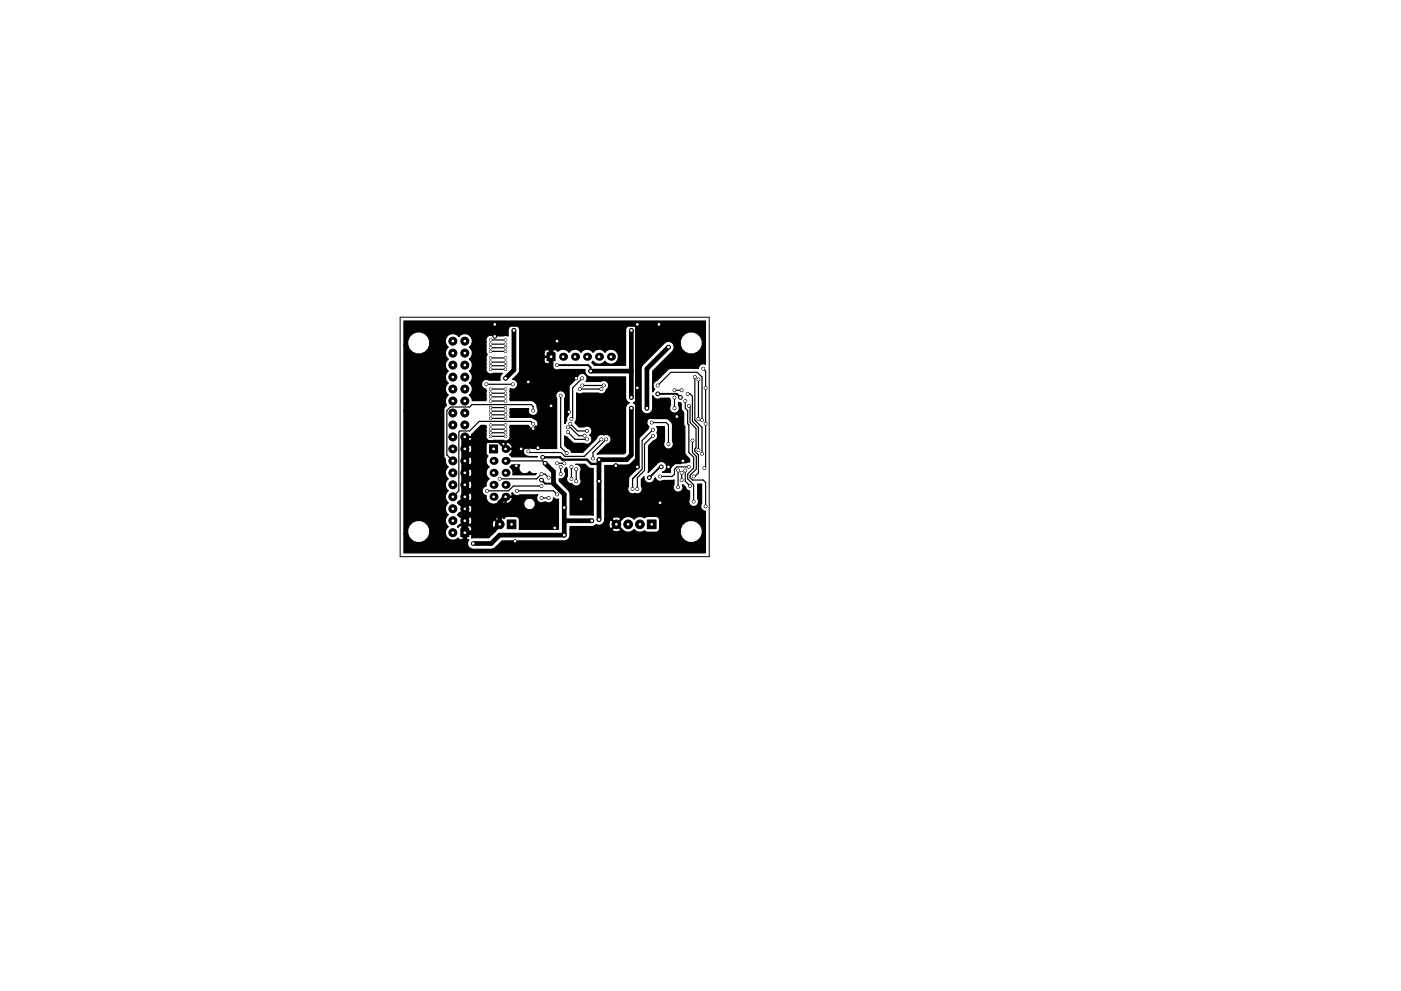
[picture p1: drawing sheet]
<svg xmlns="http://www.w3.org/2000/svg" width="297mm" height="210mm" viewBox="0 0 297 210" stroke-linecap="round" stroke-linejoin="round" font-family="sans-serif">
<path d="M84.8 67.3h65.6v50.8h-65.6z" fill="none" stroke="#000" stroke-width=".21"/>
<g fill="#000" stroke="#000" stroke-width=".21">
<path d="M116 74.8h1.7v1.7h-1.7zM103.8 94.4h1.7v1.7h-1.7zM97.7 112.2h1.7v1.7h-1.7zM107.5 110.3h1.9v1.9h-1.9zM137.3 110.3h1.8v1.9h-1.8z"/>
<circle cx="96" cy="74.9" r=".85"/>
<circle cx="96" cy="72.4" r=".85"/>
<circle cx="96" cy="77.5" r=".85"/>
<circle cx="98.6" cy="72.4" r=".85"/>
<circle cx="98.6" cy="74.9" r=".85"/>
<circle cx="98.6" cy="77.5" r=".85"/>
<circle cx="104" cy="72.1" r=".25"/>
<circle cx="104" cy="78.4" r=".25"/>
<circle cx="104" cy="73.8" r=".25"/>
<circle cx="104" cy="73" r=".25"/>
<circle cx="104" cy="75.9" r=".25"/>
<circle cx="104" cy="74.5" r=".25"/>
<circle cx="104" cy="77.6" r=".25"/>
<circle cx="104" cy="76.8" r=".25"/>
<circle cx="104.9" cy="71.4" r=".4"/>
<circle cx="104.9" cy="68.8" r=".4"/>
<circle cx="107.2" cy="75.9" r=".25"/>
<circle cx="107.2" cy="73.8" r=".25"/>
<circle cx="107.2" cy="76.8" r=".25"/>
<circle cx="107.2" cy="77.6" r=".25"/>
<circle cx="107.2" cy="73" r=".25"/>
<circle cx="107.2" cy="72.1" r=".25"/>
<circle cx="107.2" cy="74.5" r=".25"/>
<circle cx="107.2" cy="78.4" r=".25"/>
<circle cx="109" cy="70.1" r=".4"/>
<circle cx="118.1" cy="77.5" r=".3"/>
<circle cx="118.1" cy="72.4" r=".3"/>
<circle cx="125.2" cy="78.7" r=".4"/>
<circle cx="133.9" cy="70.1" r=".4"/>
<circle cx="135.1" cy="68.8" r=".4"/>
<circle cx="139.7" cy="68.8" r=".4"/>
<circle cx="141.7" cy="73.7" r=".4"/>
<circle cx="149.1" cy="78.2" r=".3"/>
<circle cx="96" cy="80" r=".85"/>
<circle cx="96" cy="87.6" r=".85"/>
<circle cx="96" cy="92.7" r=".85"/>
<circle cx="96" cy="90.2" r=".85"/>
<circle cx="96" cy="97.8" r=".85"/>
<circle cx="96" cy="82.5" r=".85"/>
<circle cx="96" cy="95.2" r=".85"/>
<circle cx="96" cy="85.1" r=".85"/>
<circle cx="98.6" cy="85.1" r=".85"/>
<circle cx="98.6" cy="92.7" r=".85"/>
<circle cx="98.6" cy="80" r=".85"/>
<circle cx="98.6" cy="97.8" r=".85"/>
<circle cx="98.6" cy="82.5" r=".85"/>
<circle cx="98.6" cy="87.6" r=".85"/>
<circle cx="98.6" cy="90.2" r=".85"/>
<circle cx="98.6" cy="95.2" r=".85"/>
<circle cx="103.1" cy="81.5" r=".3"/>
<circle cx="104" cy="88" r=".25"/>
<circle cx="104" cy="88.8" r=".25"/>
<circle cx="104" cy="84.2" r=".25"/>
<circle cx="104" cy="82.5" r=".25"/>
<circle cx="104" cy="92.6" r=".25"/>
<circle cx="104" cy="83.4" r=".25"/>
<circle cx="104" cy="91.1" r=".25"/>
<circle cx="104" cy="85.1" r=".25"/>
<circle cx="104" cy="91.8" r=".25"/>
<circle cx="104" cy="86.5" r=".25"/>
<circle cx="104" cy="90.2" r=".25"/>
<circle cx="104" cy="87.2" r=".25"/>
<circle cx="107.2" cy="92.6" r=".25"/>
<circle cx="107.2" cy="88" r=".25"/>
<circle cx="107.2" cy="91.8" r=".25"/>
<circle cx="107.2" cy="88.8" r=".25"/>
<circle cx="107.2" cy="86.5" r=".25"/>
<circle cx="107.2" cy="83.4" r=".25"/>
<circle cx="107.2" cy="91.1" r=".25"/>
<circle cx="107.2" cy="90.2" r=".25"/>
<circle cx="107.2" cy="87.2" r=".25"/>
<circle cx="107.2" cy="85.1" r=".25"/>
<circle cx="107.2" cy="84.2" r=".25"/>
<circle cx="107.2" cy="82.5" r=".25"/>
<circle cx="107.2" cy="80.3" r=".4"/>
<circle cx="108.7" cy="81.5" r=".3"/>
<circle cx="109.5" cy="98.8" r=".3"/>
<circle cx="110.5" cy="95.2" r=".3"/>
<circle cx="112" cy="81" r=".4"/>
<circle cx="112" cy="95.8" r=".3"/>
<circle cx="113" cy="87.1" r=".3"/>
<circle cx="113" cy="89.9" r=".3"/>
<circle cx="113" cy="90.9" r=".3"/>
<circle cx="114" cy="95" r=".4"/>
<circle cx="115.1" cy="97" r=".4"/>
<circle cx="115.6" cy="98.3" r=".4"/>
<circle cx="116.8" cy="86.1" r=".3"/>
<circle cx="118.1" cy="98.3" r=".3"/>
<circle cx="118.9" cy="99.1" r=".3"/>
<circle cx="118.9" cy="83.9" r=".3"/>
<circle cx="119.6" cy="98.3" r=".3"/>
<circle cx="120.1" cy="96.1" r=".3"/>
<circle cx="120.4" cy="91.7" r=".3"/>
<circle cx="120.4" cy="90.7" r=".3"/>
<circle cx="120.7" cy="87.4" r=".3"/>
<circle cx="120.9" cy="89.9" r=".3"/>
<circle cx="121.2" cy="99.1" r=".3"/>
<circle cx="121.2" cy="88.9" r=".3"/>
<circle cx="122.2" cy="99.6" r=".3"/>
<circle cx="122.2" cy="80.3" r=".3"/>
<circle cx="122.9" cy="82.5" r=".3"/>
<circle cx="123.4" cy="80.3" r=".3"/>
<circle cx="123.4" cy="81.8" r=".3"/>
<circle cx="124" cy="92.5" r=".3"/>
<circle cx="124.5" cy="93.2" r=".3"/>
<circle cx="124.5" cy="91.4" r=".3"/>
<circle cx="125.7" cy="97.3" r=".3"/>
<circle cx="127" cy="97.5" r=".4"/>
<circle cx="127.5" cy="93.2" r=".3"/>
<circle cx="127.5" cy="82.5" r=".3"/>
<circle cx="128" cy="81.8" r=".3"/>
<circle cx="128.5" cy="93.2" r=".3"/>
<circle cx="130.6" cy="98.8" r=".4"/>
<circle cx="133.9" cy="84.3" r=".4"/>
<circle cx="133.9" cy="86.6" r=".4"/>
<circle cx="135.1" cy="99.1" r=".4"/>
<circle cx="135.1" cy="82.3" r=".3"/>
<circle cx="137.2" cy="86.6" r=".4"/>
<circle cx="138.2" cy="89.7" r=".3"/>
<circle cx="138.4" cy="91.2" r=".3"/>
<circle cx="138.4" cy="92.5" r=".3"/>
<circle cx="139.4" cy="83.6" r=".4"/>
<circle cx="139.4" cy="81.8" r=".3"/>
<circle cx="140.2" cy="99.1" r=".4"/>
<circle cx="141.7" cy="99.1" r=".4"/>
<circle cx="141.7" cy="94.2" r=".3"/>
<circle cx="143" cy="86.6" r=".3"/>
<circle cx="143" cy="82.8" r=".3"/>
<circle cx="143" cy="84.3" r=".3"/>
<circle cx="143.5" cy="88.4" r=".4"/>
<circle cx="143.8" cy="99.8" r=".3"/>
<circle cx="144.3" cy="84.3" r=".4"/>
<circle cx="144.5" cy="82.8" r=".3"/>
<circle cx="144.8" cy="97.8" r=".4"/>
<circle cx="145.3" cy="85.1" r=".3"/>
<circle cx="145.3" cy="99.8" r=".3"/>
<circle cx="145.8" cy="83.6" r=".3"/>
<circle cx="146.1" cy="99.1" r=".3"/>
<circle cx="146.1" cy="86.1" r=".3"/>
<circle cx="146.8" cy="93.5" r=".3"/>
<circle cx="147.3" cy="80" r=".3"/>
<circle cx="148.1" cy="95.5" r=".3"/>
<circle cx="148.1" cy="88.9" r=".3"/>
<circle cx="148.1" cy="80.5" r=".3"/>
<circle cx="148.8" cy="96.3" r=".3"/>
<circle cx="148.8" cy="89.1" r=".3"/>
<circle cx="149.4" cy="99.3" r=".3"/>
<circle cx="149.6" cy="89.9" r=".3"/>
<circle cx="149.6" cy="82.3" r=".3"/>
<circle cx="96" cy="100.3" r=".85"/>
<circle cx="96" cy="110.5" r=".85"/>
<circle cx="96" cy="107.9" r=".85"/>
<circle cx="96" cy="105.4" r=".85"/>
<circle cx="96" cy="113" r=".85"/>
<circle cx="96" cy="102.9" r=".85"/>
<circle cx="98.6" cy="107.9" r=".85"/>
<circle cx="98.6" cy="110.5" r=".85"/>
<circle cx="98.6" cy="100.3" r=".85"/>
<circle cx="98.6" cy="105.4" r=".85"/>
<circle cx="98.6" cy="102.9" r=".85"/>
<circle cx="100.3" cy="115.3" r=".3"/>
<circle cx="103.3" cy="104.1" r=".3"/>
<circle cx="105.9" cy="101.6" r=".3"/>
<circle cx="106" cy="111.2" r=".92"/>
<circle cx="109.2" cy="114.8" r=".3"/>
<circle cx="109.6" cy="104.1" r=".3"/>
<circle cx="114.8" cy="101.8" r=".4"/>
<circle cx="114.8" cy="103.1" r=".3"/>
<circle cx="114.8" cy="105.7" r=".3"/>
<circle cx="114.8" cy="100.6" r=".3"/>
<circle cx="116.3" cy="101.3" r=".3"/>
<circle cx="116.3" cy="105.7" r=".3"/>
<circle cx="117.6" cy="112" r=".3"/>
<circle cx="118.1" cy="104.9" r=".3"/>
<circle cx="118.9" cy="100.6" r=".3"/>
<circle cx="119.6" cy="113.5" r=".4"/>
<circle cx="119.6" cy="107.7" r=".4"/>
<circle cx="121.2" cy="101.6" r=".3"/>
<circle cx="122.2" cy="102.1" r=".3"/>
<circle cx="123.2" cy="105.9" r=".3"/>
<circle cx="125.5" cy="110.5" r=".4"/>
<circle cx="127" cy="110.2" r=".4"/>
<circle cx="127" cy="102.1" r=".4"/>
<circle cx="130.7" cy="111.2" r=".92"/>
<circle cx="133.2" cy="111.2" r=".92"/>
<circle cx="134.1" cy="103.8" r=".3"/>
<circle cx="135.1" cy="103.8" r=".3"/>
<circle cx="135.7" cy="111.2" r=".92"/>
<circle cx="137.7" cy="101.3" r=".4"/>
<circle cx="140" cy="101.1" r=".3"/>
<circle cx="140" cy="106.7" r=".3"/>
<circle cx="143.8" cy="103.4" r=".3"/>
<circle cx="144.5" cy="101.8" r=".3"/>
<circle cx="144.5" cy="100.3" r=".3"/>
<circle cx="146.3" cy="103.1" r=".3"/>
<circle cx="147.1" cy="101.1" r=".3"/>
<circle cx="147.1" cy="106.4" r=".3"/>
<circle cx="149.6" cy="107.4" r=".3"/>
</g>
<g fill="#000">
<circle cx="119.4" cy="75.7" r=".85"/>
<circle cx="121.9" cy="75.7" r=".85"/>
<circle cx="124.5" cy="75.7" r=".85"/>
<circle cx="127" cy="75.7" r=".85"/>
<circle cx="129.5" cy="75.7" r=".85"/>
<circle cx="104.6" cy="97.8" r=".85"/>
<circle cx="107.2" cy="95.2" r=".85"/>
<circle cx="107.2" cy="97.8" r=".85"/>
<circle cx="104.6" cy="100.3" r=".85"/>
<circle cx="104.6" cy="102.9" r=".85"/>
<circle cx="104.6" cy="105.4" r=".85"/>
<circle cx="107.2" cy="105.4" r=".85"/>
<circle cx="107.2" cy="102.9" r=".85"/>
<circle cx="107.2" cy="100.3" r=".85"/>
</g>
<path d="M98.6 92.7h3.1l1 1h3l1.5 1.5M115.1 97h3.6l.6 .5h5.2l.8 .9h1.7" fill="none" stroke="#000" stroke-width=".5"/>
<path d="M104.9 68.8v2.6M118.1 77.5h6.6l.5 .5v.7M139.4 83.6h4.1l.8 .7M140.2 99.1h-.2l-2.3 2.2M144.8 97.8l-.5 .5h-1.3l-.8 .8h-.5M114.8 101.8l.8 .8h1.7" fill="none" stroke="#000" stroke-width=".4"/>
<g fill="none" stroke="#000" stroke-width="1">
<path d="M109 70.1v8.4l-1.8 1.8M116.8 68.8v23.9l-2 2h-3.8l-.5 .5M125.2 78.7h8.7M133.9 70.1v14.2M135.1 68.8v30.3h-4.3l-.2-.3M139.7 68.8h-45l-1 1v44.5l1 1h3.3l.6-.5v-1.8h5.6l1.8-1.8v-4.6l1.2-1.2M141.7 73.7l-4.5 4.5v8.4M114 94.7v.3M115.6 98.3l1.7 1.8v2.5l2.3 2.3v8.6h-13.7l-1.8 1.8h-3.8M116.8 80.8h-4.5l-.3 .2M133.9 86.6v9.9l-1.1 1h-5.8v12.7M135.1 88.4h8.4"/>
<path d="M119.6 110.5h5.9"/>
</g>
<g fill="none" stroke="#000" stroke-width=".25">
<path d="M104 78.4h3.2M104 77.6h3.2M104 76.8h3.2M104 75.9h3.2M104 74.5h3.2M104 73.8h3.2M104 73h3.2M104 72.1h3.2M116.8 72.4h1.3M149.1 78.2l.5 .5v20.4l-.2 .2M103.1 81.5h5.6M104 82.5h3.2"/>
<path d="M104 92.6h3.2M104 91.8h3.2M104 91.1h3.2M104 90.2h3.2M104 88.8h3.2M104 88h3.2M104 87.2h3.2M104 86.5h3.2M104 85.1h3.2M104 84.2h3.2M104 83.4h3.2M107.2 97.8h7.9l.5 .5"/>
<path d="M110.7 95v.2l-.1-.1M113 89.9l-.5-.5h-10.9l-2 2h-2.1l-.2 .3v12.4l-1.3 1.3M113 87.1v-.9l-.4-.4h-12.5l-.5 .6h-4.1l-.8 .7v9.4l1.3 1.3M116.6 90.9h.2M116.8 85.3v.8M116.8 90.4h-3.3l-.5 .5M118.1 98.3h1.5M118.9 83.9v11l1.2 1.2M118.9 99.1v1.5M120.4 90.7h.5l1.8 1.8h1.3M120.4 91.7l1.5 1.5h2.6M120.9 89.9l1.5 1.5h2.1"/>
<path d="M121.2 99.1v2.5M122.2 80.3l-1.6 1.5v5.6M122.2 99.6v2.5M122.9 82.5h4.6M123.4 80.3l-2 2v6.3l-.2 .3M123.4 81.8h4.6M127.5 93.2l-3.6 3.6h-4.1l-.9-.8h-6.6l-.3-.2M128.5 93.2l-2.8 2.8v1.3M135.1 81.8v.5M138.2 89.7h3l.5 .5v4M138.4 92.5l-1.7 1.7v5.6l-1.6 1.5v2.5M138.4 91.2l-2.3 2.3v6.1l-2 2v2.2"/>
<path d="M139.4 81.8l2.8-2.8h5.6l1 1v9.1M143 84.3v2.3M143 82.8h1.5M143.8 99.8v3.6M145.3 85.1v1.5l.5 .5v2.8l.2 .3v5.8l1.1 1v2.3l-1.3 1.3v1l1.3 1.3v3.5M145.3 99.8v2.3l1 1M145.8 83.6h.5l.5 .5v5.3l1.3 1.3v4.8M146 99.1h-2.5l-.5 .5v1l-.5 .5h-2.5M146 86.1l.3 .3v3.3l1.3 1.2v4.1l-.3 .2v.6l.8 .7v3.8l-.8 .8h-.2M146.8 93.5v2.5l.8 .8v2.7l-1.3 1.3v.5l.5 .5h2.3l.5 .6v5M147.3 80v9.1l1.5 1.6v5.6M148.1 80.5v8.4"/>
<path d="M109.6 104.1h7.7l.8 .8M114.8 103.1h-6l-1 1h-4.5M114.8 105.7h1.5M116.3 101.3l-.7-.7h-.8l-1 1h-7.9M144.5 100.3v1.5"/>
</g>
<path d="M98.6 92.7v20.3" fill="none" stroke="#000" stroke-width="1.5"/>
<path d="M85.6 68.1h64v9.2a1.01 1.01 0 0 0-1.5 .9h-6.2l-2.7 2.6a1.04 1.04 0 0 0-.8 .7 1.04 1.04 0 0 0 .4 1.1l-.4 .6v-4.5l4.2-4.2 .3-.4v-.9h1.3l.4 .9a2.37 2.37 0 0 0 3.9 0 2.37 2.37 0 0 0-1.5-3.7 2.37 2.37 0 0 0-2.8 2.8h-1.3a1.23 1.23 0 0 0-2-.4l-4.9 5-.1 8.8a1.23 1.23 0 0 0 1.3 1.2 1.23 1.23 0 0 0 1.2-1.2v-2.7l.1 .3a1.14 1.14 0 0 0 1.6 .3h1.9l.2 .4-.1 1.1a1.05 1.05 0 0 0 .9 1.7 1.05 1.05 0 0 0 .9-1.7v-.6h.4l.2 1.5 .4 .6v2.4l.3 .6v5.5l.2 .6 .8 .8v.6l-.8 .2h-1.9a1.76 1.76 0 0 0-1.4 2h-1.7l.4-.2a1.15 1.15 0 0 0 .2-1.8 1.15 1.15 0 0 0-1.8 .3l-1.8 1.7 .1-.4v-5.2l1.1-1.1a1.12 1.12 0 0 0 .7-1.7 1 1 0 0 0-.1-1.3h1.7v3.1a1.05 1.05 0 0 0 .8 1.7 1.05 1.05 0 0 0 .9-1.7v-3.5a1.76 1.76 0 0 0-1.4-1.3h-2.4a1.04 1.04 0 0 0-1.5 .3 1.04 1.04 0 0 0 .3 1.4l-.2 .5-2 2.1-.1 6.1-2 2.1-.1 1.9a1.04 1.04 0 0 0 .1 1.3 1.04 1.04 0 0 0 1.3 .2 1.04 1.04 0 0 0 1.3-.2 1.04 1.04 0 0 0 .1-1.3v-1.5l.5-.6a1.14 1.14 0 0 0 1 1.4 1.14 1.14 0 0 0 1.3-1l.2-.1 .1 .3a1.04 1.04 0 0 0 1.5 .2l2.3-.1v1a1.04 1.04 0 0 0 .8 1.6 1.04 1.04 0 0 0 1-1.5l.1-.1 .5 .5a1 1 0 0 0 .9 .8v1.7a1.05 1.05 0 0 0 .9 1.7 1.05 1.05 0 0 0 .8-1.7v-3.1h.8v4.2a1.03 1.03 0 0 0 .9 1.6v8.8h-64v-4.1h.8a2.37 2.37 0 0 0 3.7 1.5 2.37 2.37 0 0 0 0-3.9 2.37 2.37 0 0 0-3.7 1.5v.9h-.8v-26.1h8.3v9.4l.1 .3 .5 .6a1.54 1.54 0 0 0 .6 1.7 1.57 1.57 0 0 0 0 2.5 1.57 1.57 0 0 0 0 2.5 1.57 1.57 0 0 0 0 2.6 1.57 1.57 0 0 0 0 2.5 1.57 1.57 0 0 0 0 2.6 1.59 1.59 0 0 0-.3 2.3 1.59 1.59 0 0 0 2.3 0l.5 .4h.7l.1-.1v-1.2h.3v1.2l.1 .1h.6a1.22 1.22 0 0 0-.2 1.3 1.22 1.22 0 0 0 1.1 .7l4.3-.1 1.8-1.6 13.7-.1a1.32 1.32 0 0 0 .8-1.5h23.3l.4 .9a2.37 2.37 0 0 0 3.9 0 2.37 2.37 0 0 0-1.5-3.7 2.37 2.37 0 0 0-2.8 2.8h-23.3v-.9h8.9v.3a1.18 1.18 0 0 0 1.8-.3l-.9-.9-.9 .9h-8.9v-.6h4.6l.4-.1 .5-.3a1.14 1.14 0 0 0 1.5-.3h1.2v.6l.2 .5 .3 .1 .9-1h.4l.9 1a1.65 1.65 0 0 0 2.6 .1 1.61 1.61 0 0 0 2.3 .3l.6 .3h1.8a.74 .74 0 0 0 .7-.7v-1.9l-.2-.5-.5-.2h-1.8l-.7 .2a1.63 1.63 0 0 0-2.2 .4 1.64 1.64 0 0 0-2.6 .1l-.9 .9h-.4l-.9-.9-.3 .1-.2 .6h-1.2l.3-.9h1.6l.9 1 .9-1a1.09 1.09 0 0 0-1.8 0h-1.6v-11.3l5.1-.1 1.7-1.7 .1-10.4a1.2 1.2 0 0 0-.8-1.1 1.2 1.2 0 0 0 .8-1.2l-.1-14.7a1.23 1.23 0 0 0-1.4-.7 1.23 1.23 0 0 0-1 1.2v7.4h-6.6l-.5-.6 .2-.3a1.51 1.51 0 0 0 2.6 0 1.57 1.57 0 0 0 2.3 .3 1.57 1.57 0 0 0 0-2.4 1.57 1.57 0 0 0-2.3 .3 1.51 1.51 0 0 0-2.6 0 1.51 1.51 0 0 0-2.5 0 1.51 1.51 0 0 0-2.6 0 1.54 1.54 0 0 0-2.3-.3l-.5-.3h-.7l-.1 .2v2.6l.1 .3a1.03 1.03 0 0 0 .4 1 1.03 1.03 0 0 0 1.1 .1h5.5l-.1 .3a1.23 1.23 0 0 0 1.2 1.3h7.4v4.3a1.2 1.2 0 0 0 .8 1.2 1.2 1.2 0 0 0-.8 1.1v9.4l-.3 .3-5.7 .1 2.1-2.2a1.04 1.04 0 0 0 .8-1.3 1.04 1.04 0 0 0-1.5-.6 1.03 1.03 0 0 0-1.5 .7l-3 3h-2.3a1.01 1.01 0 0 0-.9-.9l-.6-.6v-2l.5 .2 1.4 1.3 2.3 .1a1.04 1.04 0 0 0 1.4-.3 1.04 1.04 0 0 0-.3-1.5 1.04 1.04 0 0 0 .3-1.4 1.04 1.04 0 0 0-1.4-.3h-1.1l-.9-1 .4-1v-5.3a.99 .99 0 0 0 1.2 .1h3.4a1.1 1.1 0 0 0 1.7-.7 1.04 1.04 0 0 0 .3-1.5 1.04 1.04 0 0 0-1.5-.3h-3.2l.1-.1a1.05 1.05 0 0 0-.5-1.5 1.05 1.05 0 0 0-1.4 .8l-1.8 1.9v6a.99 .99 0 0 0-.4 1.2l-.5 .7v-5.4a1.04 1.04 0 0 0-.8-1.6 1.04 1.04 0 0 0-.9 1.6l.1 10.7h-5.2l-.3-.3a1.07 1.07 0 0 0-1.6 .7 1.07 1.07 0 0 0 1.3 1.3h1.6h-5.4l-.5-.4 .6-.9-.1-.2h-1.5l.1-1.5h.2v1.2h1.2a1.08 1.08 0 0 0-1.4-1.2l-.3-.1-.6 .4-.4-.5h-2a.74 .74 0 0 0-.7 .7v1.7l.4 .6a1.51 1.51 0 0 0 .2 2.4 1.51 1.51 0 0 0 0 2.5 1.4 1.4 0 0 0-.6 1.5 1.04 1.04 0 0 0-.9 1 1.04 1.04 0 0 0 .9 1.1 1.57 1.57 0 0 0 1 1.7 1.57 1.57 0 0 0 1.9-.7l.8 .6 .3-.1v-1.2h.2v1.2a.99 .99 0 0 0 1.2-1.2h-1.5v-.2h1.5l.1-.3-.1-.3 .1-.2a1.02 1.02 0 0 0 1.6 .5h3.8l-.1 .1a1.04 1.04 0 0 0 .2 1.3 1.04 1.04 0 0 0 1.3 .1h.3a1.03 1.03 0 0 0 1.1 .1 1.03 1.03 0 0 0 .6-1 .94 .94 0 0 0 1 .3v6.4h-8.3v-2a.74 .74 0 0 0-.7-.7h-1.9l-.5 .2-.2 .3v-.2a1.18 1.18 0 0 0-1.8 .2l1.2 1.2-1.2 1 .1 .3-1.5 1.5-3.6 .1v-.9l-.1-.1h-1.5v-.3h1.5l.1-.2-.1-.9-.5-.3-.8-.8-.9 .8-.4 .1-.2 .3-.1-.1 1.4-1.3h.3l.9 .8h.2l.1-.3h4.5v.6l.2 .5 .3 .1 .9-1-.9-.9-.3 .1-.2 .6h-4.5l.1-.9-.2-.4-.2-.1-.9 .9h-.3l-1.4-1.3 .2-.2h.5v.4l.9 .9 .8-.9v-.4l-.8-.9-.9 .9h-.5l1.2-1.1h.3l.9 .9 .2-.1 .2-.5-.1-1h11.1a1.25 1.25 0 0 0 2 .8 1.25 1.25 0 0 0 0-2.1 1.25 1.25 0 0 0-2 .8v.5l-11.4-.1-.9 .8h-.3l-1.4-1.2 .2-.3h.5v.5l.9 .9 .8-.9v-.5l-.8-.8-.9 .8h-.5l.2-.2 .1 .1 .9-.9h.3l.9 .9 .2-.1a1.1 1.1 0 0 0-.2-1.7l-.9 .9h-.3l1-1v-.5l-1-1h.3l.9 .8a1.02 1.02 0 0 0 0-1.7l-.9 .9h-.3l1-1.1v-.4l-1-1.1h.3l.9 .9a1.02 1.02 0 0 0 0-1.7l-.9 .8h-.3l1-1v-.5l-1-1h.3l.9 .8a1.02 1.02 0 0 0 0-1.7l-.9 .9h-.3l1-1.1v-.4l-1-1 .3-.1 .9 .9a1.02 1.02 0 0 0 0-1.7l-.9 .8h-.3l1-1v-.5l-1-1 .2-.2 1 1.1 .2-.1 .2-.6v-.7l2-1.9h1l.1 1.9a.97 .97 0 0 0 .3 1.1 .97 .97 0 0 0 1.1 .1h2.2l.3 .2a.98 .98 0 0 0 1-.4 .98 .98 0 0 0 .1-1l.1-1.9h3.9l.1 .2a1.07 1.07 0 0 0 1.7-.1 1.07 1.07 0 0 0-.8-1.6l-.6-.2h-4.3v-1.9h3.9a1.04 1.04 0 0 0 1 1.5 1.04 1.04 0 0 0 .8-1.7 1.47 1.47 0 0 0-1.3-1.5h-4.4l-.1-2 .1-.6 .3 .2a1.04 1.04 0 0 0 1.3-1 1.04 1.04 0 0 0-1.1-1.1l1.4-1.6 .1-2.9h5.2v.7l.2 .4 1 .1 .1-.2v-1.2h-1.2l-.1 .2h-5.2v-1.3h5.2v.7l.1 .2h1.2v-1.2l-.1-.2-1 .1-.2 .4h-5.2v-4.6a1.23 1.23 0 0 0-1.2-1.2 1.23 1.23 0 0 0-1.3 1.2v1.2l-.3-.1-.7 .1h-2.2l-.3-.1a.98 .98 0 0 0-1 .3 .98 .98 0 0 0-.1 1.1v1.6a.9 .9 0 0 0 .2 1 .91 .91 0 0 0-.2 1.2v1.6a.97 .97 0 0 0 .3 1.1 .97 .97 0 0 0 1.1 .1h2l-.4 .6-.1 .9h-2.3a1.04 1.04 0 0 0-1.6 .5 1.04 1.04 0 0 0 .9 1.4v2.4h-2.9l-.2-.8-.4-.4a1.57 1.57 0 0 0 0-2.5 1.57 1.57 0 0 0 0-2.6 1.57 1.57 0 0 0 0-2.5 1.57 1.57 0 0 0 0-2.5 1.59 1.59 0 0 0 .2-2.5 1.59 1.59 0 0 0-2.4 .2 1.59 1.59 0 0 0-2.4-.2 1.59 1.59 0 0 0 .2 2.5 1.57 1.57 0 0 0 0 2.5 1.57 1.57 0 0 0 0 2.5 1.57 1.57 0 0 0 0 2.6 1.57 1.57 0 0 0 0 2.5 1.58 1.58 0 0 0-.4 2.2l-.6 .5-.2 .6h-8.3v-13.9h.8a2.37 2.37 0 0 0 3.7 1.5 2.37 2.37 0 0 0 0-3.9 2.37 2.37 0 0 0-3.7 1.5v.9h-.8zM108.5 98.6h1.7a1.24 1.24 0 0 0 .4 1.7 1.24 1.24 0 0 0 1.7-.3 1.18 1.18 0 0 0 1.4 .4l-.3 .3h-4.7a1.44 1.44 0 0 0-.6-1.6zM119.9 99.3l.2-.1 .2 .5v1.3a1.09 1.09 0 0 0 0 1.2 1.09 1.09 0 0 0 1 .5 1.04 1.04 0 0 0 1.5 .3 1.04 1.04 0 0 0 .2-1.5v-1.3a1.06 1.06 0 0 0 .1-1.2 1.06 1.06 0 0 0-1.1-.5h2.1a1.64 1.64 0 0 0 1.7 .9v9.9h-4.9l-.1-4.9-2.2-2.3v-.5a1.03 1.03 0 0 0 1.1-.4 1.03 1.03 0 0 0 0-1.2z" fill="#000" stroke="#000" stroke-width=".25"/>
<g fill="#fff" stroke="#fff" stroke-width=".21">
<circle cx="115.1" cy="97" r=".17"/>
<circle cx="127" cy="102.1" r=".17"/>
<circle cx="140.2" cy="99.1" r=".17"/>
<circle cx="137.7" cy="101.3" r=".17"/>
<circle cx="127" cy="110.2" r=".17"/>
<circle cx="133.9" cy="86.6" r=".17"/>
<circle cx="137.2" cy="86.6" r=".17"/>
<circle cx="141.7" cy="73.7" r=".17"/>
<circle cx="127" cy="97.5" r=".17"/>
<circle cx="114" cy="95" r=".17"/>
<circle cx="123.2" cy="105.9" r=".17"/>
<circle cx="135.1" cy="82.3" r=".17"/>
<circle cx="116.8" cy="86.1" r=".17"/>
<circle cx="118.1" cy="72.4" r=".17"/>
<circle cx="109.5" cy="98.8" r=".17"/>
<circle cx="110.5" cy="95.2" r=".17"/>
<circle cx="109.2" cy="114.8" r=".17"/>
<circle cx="117.6" cy="112" r=".17"/>
<circle cx="140" cy="106.7" r=".17"/>
<circle cx="141.7" cy="99.1" r=".17"/>
<circle cx="144.8" cy="97.8" r=".17"/>
<circle cx="113" cy="90.9" r=".17"/>
<circle cx="104.9" cy="68.8" r=".17"/>
<circle cx="104.9" cy="71.4" r=".17"/>
<circle cx="143.5" cy="88.4" r=".17"/>
<circle cx="130.6" cy="98.8" r=".17"/>
<circle cx="135.1" cy="99.1" r=".17"/>
<circle cx="112" cy="81" r=".17"/>
<circle cx="139.7" cy="68.8" r=".17"/>
<circle cx="135.1" cy="68.8" r=".17"/>
<circle cx="120.6" cy="87.4" r=".17"/>
<circle cx="122.2" cy="80.3" r=".17"/>
<circle cx="100.3" cy="115.3" r=".17"/>
<circle cx="118.1" cy="77.5" r=".17"/>
<circle cx="133.9" cy="84.3" r=".17"/>
<circle cx="139.4" cy="83.6" r=".17"/>
<circle cx="144.3" cy="84.3" r=".17"/>
<circle cx="133.9" cy="70.1" r=".17"/>
<circle cx="125.2" cy="78.7" r=".17"/>
<circle cx="109" cy="70.1" r=".17"/>
<circle cx="107.2" cy="80.3" r=".17"/>
<circle cx="114.8" cy="101.8" r=".17"/>
<circle cx="115.6" cy="98.3" r=".17"/>
<circle cx="125.5" cy="110.5" r=".17"/>
<circle cx="119.6" cy="107.7" r=".17"/>
<circle cx="119.6" cy="113.5" r=".17"/>
<circle cx="123.4" cy="80.3" r=".17"/>
<circle cx="121.2" cy="88.9" r=".17"/>
<circle cx="146" cy="99.1" r=".17"/>
<circle cx="140" cy="101.1" r=".17"/>
<circle cx="149.6" cy="89.9" r=".17"/>
<circle cx="149.4" cy="99.3" r=".17"/>
<circle cx="149.1" cy="78.2" r=".17"/>
<circle cx="149.6" cy="82.3" r=".17"/>
<circle cx="147.1" cy="101.1" r=".17"/>
<circle cx="146" cy="86.1" r=".17"/>
<circle cx="145.3" cy="85.1" r=".17"/>
<circle cx="147.1" cy="106.4" r=".17"/>
<circle cx="143" cy="84.3" r=".17"/>
<circle cx="143" cy="86.6" r=".17"/>
<circle cx="143.8" cy="99.8" r=".17"/>
<circle cx="143.8" cy="103.4" r=".17"/>
<circle cx="148.1" cy="95.5" r=".17"/>
<circle cx="145.8" cy="83.6" r=".17"/>
<circle cx="143" cy="82.8" r=".17"/>
<circle cx="144.5" cy="82.8" r=".17"/>
<circle cx="148.8" cy="89.1" r=".17"/>
<circle cx="139.4" cy="81.8" r=".17"/>
<circle cx="127.5" cy="82.5" r=".17"/>
<circle cx="122.9" cy="82.5" r=".17"/>
<circle cx="128" cy="81.8" r=".17"/>
<circle cx="123.4" cy="81.8" r=".17"/>
<circle cx="124.5" cy="91.4" r=".17"/>
<circle cx="120.9" cy="89.9" r=".17"/>
<circle cx="124" cy="92.5" r=".17"/>
<circle cx="120.4" cy="90.7" r=".17"/>
<circle cx="124.5" cy="93.2" r=".17"/>
<circle cx="120.4" cy="91.7" r=".17"/>
<circle cx="104" cy="92.6" r=".15"/>
<circle cx="107.2" cy="92.6" r=".15"/>
<circle cx="104" cy="91.8" r=".15"/>
<circle cx="107.2" cy="91.8" r=".15"/>
<circle cx="113" cy="89.9" r=".17"/>
<circle cx="104" cy="91.1" r=".15"/>
<circle cx="107.2" cy="91.1" r=".15"/>
<circle cx="104" cy="90.2" r=".15"/>
<circle cx="107.2" cy="90.2" r=".15"/>
<circle cx="113" cy="87.1" r=".17"/>
<circle cx="104" cy="88.8" r=".15"/>
<circle cx="107.2" cy="88.8" r=".15"/>
<circle cx="104" cy="88" r=".15"/>
<circle cx="107.2" cy="88" r=".15"/>
<circle cx="104" cy="87.2" r=".15"/>
<circle cx="107.2" cy="87.2" r=".15"/>
<circle cx="104" cy="86.5" r=".15"/>
<circle cx="107.2" cy="86.5" r=".15"/>
<circle cx="104" cy="85.1" r=".15"/>
<circle cx="107.2" cy="85.1" r=".15"/>
<circle cx="104" cy="84.2" r=".15"/>
<circle cx="107.2" cy="84.2" r=".15"/>
<circle cx="104" cy="83.4" r=".15"/>
<circle cx="107.2" cy="83.4" r=".15"/>
<circle cx="104" cy="82.5" r=".15"/>
<circle cx="107.2" cy="82.5" r=".15"/>
<circle cx="108.7" cy="81.5" r=".17"/>
<circle cx="103.1" cy="81.5" r=".17"/>
<circle cx="104" cy="78.4" r=".15"/>
<circle cx="107.2" cy="78.4" r=".15"/>
<circle cx="104" cy="77.6" r=".15"/>
<circle cx="107.2" cy="77.6" r=".15"/>
<circle cx="104" cy="76.8" r=".15"/>
<circle cx="107.2" cy="76.8" r=".15"/>
<circle cx="104" cy="75.9" r=".15"/>
<circle cx="107.2" cy="75.9" r=".15"/>
<circle cx="104" cy="74.5" r=".15"/>
<circle cx="107.2" cy="74.5" r=".15"/>
<circle cx="104" cy="73.8" r=".15"/>
<circle cx="107.2" cy="73.8" r=".15"/>
<circle cx="104" cy="73" r=".15"/>
<circle cx="107.2" cy="73" r=".15"/>
<circle cx="104" cy="72.1" r=".15"/>
<circle cx="107.2" cy="72.1" r=".15"/>
<circle cx="148.1" cy="80.5" r=".17"/>
<circle cx="148.1" cy="88.9" r=".17"/>
<circle cx="144.5" cy="100.3" r=".17"/>
<circle cx="144.5" cy="101.8" r=".17"/>
<circle cx="145.3" cy="99.8" r=".17"/>
<circle cx="146.3" cy="103.1" r=".17"/>
<circle cx="149.6" cy="107.4" r=".17"/>
<circle cx="146.8" cy="93.5" r=".17"/>
<circle cx="147.3" cy="80" r=".17"/>
<circle cx="148.8" cy="96.3" r=".17"/>
<circle cx="127.5" cy="93.2" r=".17"/>
<circle cx="112" cy="95.8" r=".17"/>
<circle cx="122.2" cy="99.6" r=".17"/>
<circle cx="122.2" cy="102.1" r=".17"/>
<circle cx="109.6" cy="104.1" r=".17"/>
<circle cx="118.1" cy="104.9" r=".17"/>
<circle cx="118.9" cy="99.1" r=".17"/>
<circle cx="118.9" cy="100.6" r=".17"/>
<circle cx="105.9" cy="101.6" r=".17"/>
<circle cx="118.1" cy="98.3" r=".17"/>
<circle cx="119.6" cy="98.3" r=".17"/>
<circle cx="114.8" cy="100.6" r=".17"/>
<circle cx="116.3" cy="101.3" r=".17"/>
<circle cx="114.8" cy="105.7" r=".17"/>
<circle cx="116.3" cy="105.7" r=".17"/>
<circle cx="121.2" cy="99.1" r=".17"/>
<circle cx="121.2" cy="101.6" r=".17"/>
<circle cx="120.1" cy="96.1" r=".17"/>
<circle cx="118.9" cy="83.9" r=".17"/>
<circle cx="103.3" cy="104.1" r=".17"/>
<circle cx="114.8" cy="103.1" r=".17"/>
<circle cx="141.7" cy="94.2" r=".17"/>
<circle cx="138.2" cy="89.7" r=".17"/>
<circle cx="138.4" cy="92.5" r=".17"/>
<circle cx="135.1" cy="103.8" r=".17"/>
<circle cx="138.4" cy="91.2" r=".17"/>
<circle cx="134.1" cy="103.8" r=".17"/>
<circle cx="125.7" cy="97.3" r=".17"/>
<circle cx="128.5" cy="93.2" r=".17"/>
<circle cx="88.8" cy="112.8" r=".17"/>
<circle cx="146.6" cy="112.8" r=".17"/>
<circle cx="146.6" cy="72.8" r=".17"/>
<circle cx="88.8" cy="72.8" r=".17"/>
<circle cx="104.6" cy="95.2" r=".17"/>
<circle cx="107.2" cy="95.2" r=".17"/>
<circle cx="104.6" cy="97.8" r=".17"/>
<circle cx="107.2" cy="97.8" r=".17"/>
<circle cx="104.6" cy="100.3" r=".17"/>
<circle cx="107.2" cy="100.3" r=".17"/>
<circle cx="104.6" cy="102.9" r=".17"/>
<circle cx="107.2" cy="102.9" r=".17"/>
<circle cx="104.6" cy="105.4" r=".17"/>
<circle cx="107.2" cy="105.4" r=".17"/>
<circle cx="111.3" cy="99.3" r=".17"/>
<circle cx="113.3" cy="99.3" r=".17"/>
<circle cx="112.3" cy="106.9" r=".17"/>
<circle cx="108.5" cy="111.2" r=".17"/>
<circle cx="106" cy="111.2" r=".17"/>
<circle cx="98.6" cy="113" r=".17"/>
<circle cx="96" cy="113" r=".17"/>
<circle cx="98.6" cy="110.5" r=".17"/>
<circle cx="96" cy="110.5" r=".17"/>
<circle cx="98.6" cy="107.9" r=".17"/>
<circle cx="96" cy="107.9" r=".17"/>
<circle cx="98.6" cy="105.4" r=".17"/>
<circle cx="96" cy="105.4" r=".17"/>
<circle cx="98.6" cy="102.9" r=".17"/>
<circle cx="96" cy="102.9" r=".17"/>
<circle cx="98.6" cy="100.3" r=".17"/>
<circle cx="96" cy="100.3" r=".17"/>
<circle cx="98.6" cy="97.8" r=".17"/>
<circle cx="96" cy="97.8" r=".17"/>
<circle cx="98.6" cy="95.2" r=".17"/>
<circle cx="96" cy="95.2" r=".17"/>
<circle cx="98.6" cy="92.7" r=".17"/>
<circle cx="96" cy="92.7" r=".17"/>
<circle cx="98.6" cy="90.2" r=".17"/>
<circle cx="96" cy="90.2" r=".17"/>
<circle cx="98.6" cy="87.6" r=".17"/>
<circle cx="96" cy="87.6" r=".17"/>
<circle cx="98.6" cy="85.1" r=".17"/>
<circle cx="96" cy="85.1" r=".17"/>
<circle cx="98.6" cy="82.5" r=".17"/>
<circle cx="96" cy="82.5" r=".17"/>
<circle cx="98.6" cy="80" r=".17"/>
<circle cx="96" cy="80" r=".17"/>
<circle cx="98.6" cy="77.5" r=".17"/>
<circle cx="96" cy="77.5" r=".17"/>
<circle cx="98.6" cy="74.9" r=".17"/>
<circle cx="96" cy="74.9" r=".17"/>
<circle cx="98.6" cy="72.4" r=".17"/>
<circle cx="96" cy="72.4" r=".17"/>
<circle cx="116.8" cy="75.7" r=".17"/>
<circle cx="119.4" cy="75.7" r=".17"/>
<circle cx="121.9" cy="75.7" r=".17"/>
<circle cx="124.5" cy="75.7" r=".17"/>
<circle cx="127" cy="75.7" r=".17"/>
<circle cx="129.5" cy="75.7" r=".17"/>
<circle cx="138.2" cy="111.2" r=".17"/>
<circle cx="135.7" cy="111.2" r=".17"/>
<circle cx="133.2" cy="111.2" r=".17"/>
<circle cx="130.7" cy="111.2" r=".18"/>
</g>
</svg>
